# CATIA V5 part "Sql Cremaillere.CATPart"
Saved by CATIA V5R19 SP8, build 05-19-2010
Part number: Sql Cremaillere
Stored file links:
  G:\EU_thinkMotion\CFAO_2010\MMS_groupe3\MMS_groupe3\rdalborgo\rdalborgo\Sql Cremaillere.CATPart

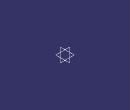
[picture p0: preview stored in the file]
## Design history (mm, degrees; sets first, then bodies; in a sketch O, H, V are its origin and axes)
Body1 (main body)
